VERSION 5.7 ;
  NOWIREEXTENSIONATPIN ON ;
  DIVIDERCHAR "/" ;
  BUSBITCHARS "[]" ;
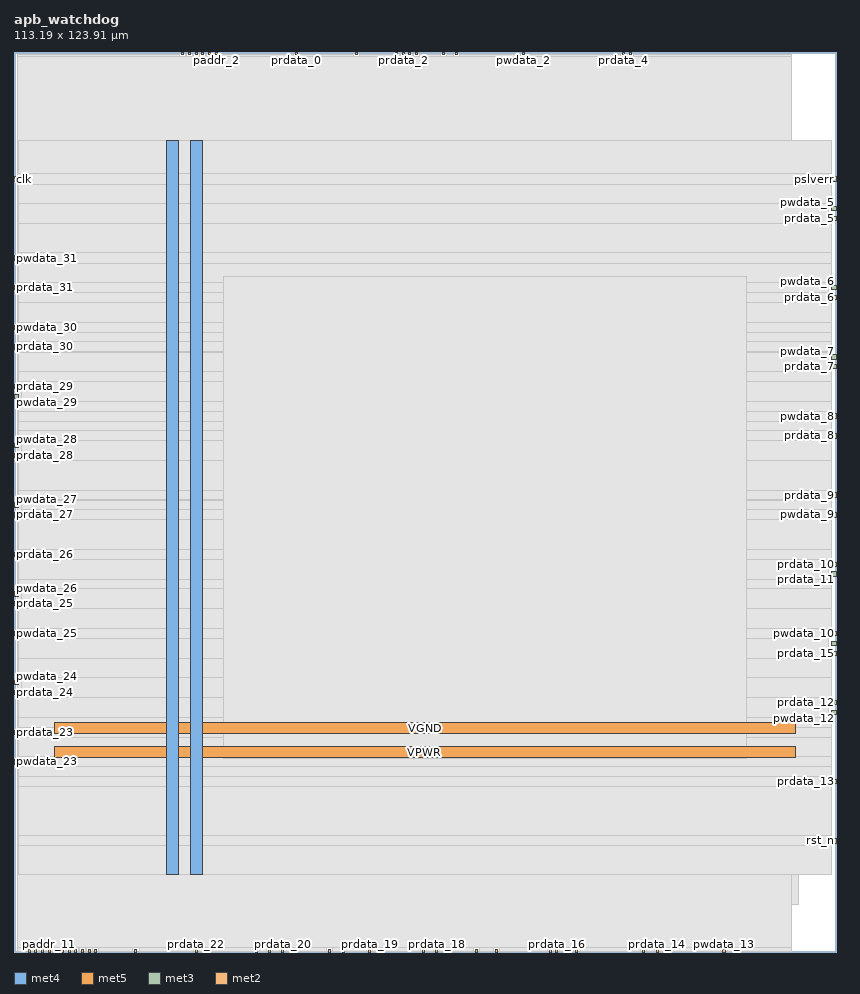
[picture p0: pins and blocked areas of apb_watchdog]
MACRO apb_watchdog
  CLASS BLOCK ;
  FOREIGN apb_watchdog ;
  ORIGIN 0.000 0.000 ;
  SIZE 113.190 BY 123.910 ;
  PIN VGND
    DIRECTION INOUT ;
    USE GROUND ;
    PORT
      LAYER met4 ;
        RECT 24.340 10.640 25.940 111.760 ;
    END
    PORT
      LAYER met5 ;
        RECT 5.520 30.030 107.640 31.630 ;
    END
  END VGND
  PIN VPWR
    DIRECTION INOUT ;
    USE POWER ;
    PORT
      LAYER met4 ;
        RECT 21.040 10.640 22.640 111.760 ;
    END
    PORT
      LAYER met5 ;
        RECT 5.520 26.730 107.640 28.330 ;
    END
  END VPWR
  PIN clk
    DIRECTION INPUT ;
    USE SIGNAL ;
    ANTENNAGATEAREA 1.286700 ;
    ANTENNADIFFAREA 0.434700 ;
    PORT
      LAYER met3 ;
        RECT 0.000 106.120 0.600 106.720 ;
    END
  END clk
  PIN paddr_0
    DIRECTION INPUT ;
    USE SIGNAL ;
    PORT
      LAYER met2 ;
        RECT 1.930 0.000 2.210 0.280 ;
    END
  END paddr_0
  PIN paddr_1
    DIRECTION INPUT ;
    USE SIGNAL ;
    PORT
      LAYER met2 ;
        RECT 2.850 0.000 3.130 0.280 ;
    END
  END paddr_1
  PIN paddr_10
    DIRECTION INPUT ;
    USE SIGNAL ;
    PORT
      LAYER met2 ;
        RECT 3.770 0.000 4.050 0.280 ;
    END
  END paddr_10
  PIN paddr_11
    DIRECTION INPUT ;
    USE SIGNAL ;
    PORT
      LAYER met2 ;
        RECT 4.690 0.000 4.970 0.280 ;
    END
  END paddr_11
  PIN paddr_2
    DIRECTION INPUT ;
    USE SIGNAL ;
    ANTENNAGATEAREA 0.647700 ;
    ANTENNADIFFAREA 0.434700 ;
    PORT
      LAYER met2 ;
        RECT 27.690 123.630 27.970 123.910 ;
    END
  END paddr_2
  PIN paddr_3
    DIRECTION INPUT ;
    USE SIGNAL ;
    ANTENNAGATEAREA 0.647700 ;
    ANTENNADIFFAREA 0.434700 ;
    PORT
      LAYER met2 ;
        RECT 26.770 123.630 27.050 123.910 ;
    END
  END paddr_3
  PIN paddr_4
    DIRECTION INPUT ;
    USE SIGNAL ;
    ANTENNAGATEAREA 0.647700 ;
    ANTENNADIFFAREA 0.434700 ;
    PORT
      LAYER met2 ;
        RECT 25.850 123.630 26.130 123.910 ;
    END
  END paddr_4
  PIN paddr_5
    DIRECTION INPUT ;
    USE SIGNAL ;
    PORT
      LAYER met2 ;
        RECT 5.610 0.000 5.890 0.280 ;
    END
  END paddr_5
  PIN paddr_6
    DIRECTION INPUT ;
    USE SIGNAL ;
    PORT
      LAYER met2 ;
        RECT 6.530 0.000 6.810 0.280 ;
    END
  END paddr_6
  PIN paddr_7
    DIRECTION INPUT ;
    USE SIGNAL ;
    PORT
      LAYER met2 ;
        RECT 7.450 0.000 7.730 0.280 ;
    END
  END paddr_7
  PIN paddr_8
    DIRECTION INPUT ;
    USE SIGNAL ;
    PORT
      LAYER met2 ;
        RECT 8.370 0.000 8.650 0.280 ;
    END
  END paddr_8
  PIN paddr_9
    DIRECTION INPUT ;
    USE SIGNAL ;
    PORT
      LAYER met2 ;
        RECT 9.290 0.000 9.570 0.280 ;
    END
  END paddr_9
  PIN penable
    DIRECTION INPUT ;
    USE SIGNAL ;
    ANTENNAGATEAREA 0.647700 ;
    ANTENNADIFFAREA 0.434700 ;
    PORT
      LAYER met2 ;
        RECT 24.010 123.630 24.290 123.910 ;
    END
  END penable
  PIN prdata_0
    DIRECTION OUTPUT ;
    USE SIGNAL ;
    ANTENNAGATEAREA 0.434700 ;
    ANTENNADIFFAREA 1.137600 ;
    PORT
      LAYER met2 ;
        RECT 38.730 123.630 39.010 123.910 ;
    END
  END prdata_0
  PIN prdata_1
    DIRECTION OUTPUT ;
    USE SIGNAL ;
    ANTENNAGATEAREA 0.434700 ;
    ANTENNADIFFAREA 1.137600 ;
    PORT
      LAYER met2 ;
        RECT 52.530 123.630 52.810 123.910 ;
    END
  END prdata_1
  PIN prdata_10
    DIRECTION OUTPUT ;
    USE SIGNAL ;
    ANTENNAGATEAREA 0.434700 ;
    ANTENNADIFFAREA 1.137600 ;
    PORT
      LAYER met3 ;
        RECT 112.590 53.080 113.190 53.680 ;
    END
  END prdata_10
  PIN prdata_11
    DIRECTION OUTPUT ;
    USE SIGNAL ;
    ANTENNAGATEAREA 0.434700 ;
    ANTENNADIFFAREA 1.137600 ;
    PORT
      LAYER met3 ;
        RECT 112.590 51.720 113.190 52.320 ;
    END
  END prdata_11
  PIN prdata_12
    DIRECTION OUTPUT ;
    USE SIGNAL ;
    ANTENNAGATEAREA 0.434700 ;
    ANTENNADIFFAREA 1.137600 ;
    PORT
      LAYER met3 ;
        RECT 112.590 34.040 113.190 34.640 ;
    END
  END prdata_12
  PIN prdata_13
    DIRECTION OUTPUT ;
    USE SIGNAL ;
    ANTENNAGATEAREA 0.434700 ;
    ANTENNADIFFAREA 1.137600 ;
    PORT
      LAYER met3 ;
        RECT 112.590 23.160 113.190 23.760 ;
    END
  END prdata_13
  PIN prdata_14
    DIRECTION OUTPUT ;
    USE SIGNAL ;
    ANTENNAGATEAREA 0.434700 ;
    ANTENNADIFFAREA 1.137600 ;
    PORT
      LAYER met2 ;
        RECT 88.410 0.000 88.690 0.280 ;
    END
  END prdata_14
  PIN prdata_15
    DIRECTION OUTPUT ;
    USE SIGNAL ;
    ANTENNAGATEAREA 0.434700 ;
    ANTENNADIFFAREA 1.137600 ;
    PORT
      LAYER met3 ;
        RECT 112.590 40.840 113.190 41.440 ;
    END
  END prdata_15
  PIN prdata_16
    DIRECTION OUTPUT ;
    USE SIGNAL ;
    ANTENNAGATEAREA 0.434700 ;
    ANTENNADIFFAREA 1.137600 ;
    PORT
      LAYER met2 ;
        RECT 74.610 0.000 74.890 0.280 ;
    END
  END prdata_16
  PIN prdata_17
    DIRECTION OUTPUT ;
    USE SIGNAL ;
    ANTENNAGATEAREA 0.434700 ;
    ANTENNADIFFAREA 1.137600 ;
    PORT
      LAYER met2 ;
        RECT 66.330 0.000 66.610 0.280 ;
    END
  END prdata_17
  PIN prdata_18
    DIRECTION OUTPUT ;
    USE SIGNAL ;
    ANTENNAGATEAREA 0.434700 ;
    ANTENNADIFFAREA 1.137600 ;
    PORT
      LAYER met2 ;
        RECT 58.050 0.000 58.330 0.280 ;
    END
  END prdata_18
  PIN prdata_19
    DIRECTION OUTPUT ;
    USE SIGNAL ;
    ANTENNAGATEAREA 0.434700 ;
    ANTENNADIFFAREA 1.137600 ;
    PORT
      LAYER met2 ;
        RECT 48.850 0.000 49.130 0.280 ;
    END
  END prdata_19
  PIN prdata_2
    DIRECTION OUTPUT ;
    USE SIGNAL ;
    ANTENNAGATEAREA 0.434700 ;
    ANTENNADIFFAREA 1.137600 ;
    PORT
      LAYER met2 ;
        RECT 53.450 123.630 53.730 123.910 ;
    END
  END prdata_2
  PIN prdata_20
    DIRECTION OUTPUT ;
    USE SIGNAL ;
    ANTENNAGATEAREA 0.434700 ;
    ANTENNADIFFAREA 1.137600 ;
    PORT
      LAYER met2 ;
        RECT 36.890 0.000 37.170 0.280 ;
    END
  END prdata_20
  PIN prdata_21
    DIRECTION OUTPUT ;
    USE SIGNAL ;
    ANTENNAGATEAREA 0.434700 ;
    ANTENNADIFFAREA 1.137600 ;
    PORT
      LAYER met2 ;
        RECT 43.330 0.000 43.610 0.280 ;
    END
  END prdata_21
  PIN prdata_22
    DIRECTION OUTPUT ;
    USE SIGNAL ;
    ANTENNAGATEAREA 0.434700 ;
    ANTENNADIFFAREA 1.137600 ;
    PORT
      LAYER met2 ;
        RECT 24.930 0.000 25.210 0.280 ;
    END
  END prdata_22
  PIN prdata_23
    DIRECTION OUTPUT ;
    USE SIGNAL ;
    ANTENNAGATEAREA 0.434700 ;
    ANTENNADIFFAREA 1.137600 ;
    PORT
      LAYER met3 ;
        RECT 0.000 29.960 0.600 30.560 ;
    END
  END prdata_23
  PIN prdata_24
    DIRECTION OUTPUT ;
    USE SIGNAL ;
    ANTENNAGATEAREA 0.434700 ;
    ANTENNADIFFAREA 1.137600 ;
    PORT
      LAYER met3 ;
        RECT 0.000 35.400 0.600 36.000 ;
    END
  END prdata_24
  PIN prdata_25
    DIRECTION OUTPUT ;
    USE SIGNAL ;
    ANTENNAGATEAREA 0.434700 ;
    ANTENNADIFFAREA 1.137600 ;
    PORT
      LAYER met3 ;
        RECT 0.000 47.640 0.600 48.240 ;
    END
  END prdata_25
  PIN prdata_26
    DIRECTION OUTPUT ;
    USE SIGNAL ;
    ANTENNAGATEAREA 0.434700 ;
    ANTENNADIFFAREA 1.137600 ;
    PORT
      LAYER met3 ;
        RECT 0.000 54.440 0.600 55.040 ;
    END
  END prdata_26
  PIN prdata_27
    DIRECTION OUTPUT ;
    USE SIGNAL ;
    ANTENNAGATEAREA 0.434700 ;
    ANTENNADIFFAREA 1.137600 ;
    PORT
      LAYER met3 ;
        RECT 0.000 59.880 0.600 60.480 ;
    END
  END prdata_27
  PIN prdata_28
    DIRECTION OUTPUT ;
    USE SIGNAL ;
    ANTENNAGATEAREA 0.434700 ;
    ANTENNADIFFAREA 1.137600 ;
    PORT
      LAYER met3 ;
        RECT 0.000 68.040 0.600 68.640 ;
    END
  END prdata_28
  PIN prdata_29
    DIRECTION OUTPUT ;
    USE SIGNAL ;
    ANTENNAGATEAREA 0.434700 ;
    ANTENNADIFFAREA 1.137600 ;
    PORT
      LAYER met3 ;
        RECT 0.000 77.560 0.600 78.160 ;
    END
  END prdata_29
  PIN prdata_3
    DIRECTION OUTPUT ;
    USE SIGNAL ;
    ANTENNAGATEAREA 0.434700 ;
    ANTENNADIFFAREA 1.137600 ;
    PORT
      LAYER met2 ;
        RECT 55.290 123.630 55.570 123.910 ;
    END
  END prdata_3
  PIN prdata_30
    DIRECTION OUTPUT ;
    USE SIGNAL ;
    ANTENNAGATEAREA 0.434700 ;
    ANTENNADIFFAREA 1.137600 ;
    PORT
      LAYER met3 ;
        RECT 0.000 83.000 0.600 83.600 ;
    END
  END prdata_30
  PIN prdata_31
    DIRECTION OUTPUT ;
    USE SIGNAL ;
    ANTENNAGATEAREA 0.434700 ;
    ANTENNADIFFAREA 1.137600 ;
    PORT
      LAYER met3 ;
        RECT 0.000 91.160 0.600 91.760 ;
    END
  END prdata_31
  PIN prdata_4
    DIRECTION OUTPUT ;
    USE SIGNAL ;
    ANTENNAGATEAREA 0.434700 ;
    ANTENNADIFFAREA 1.137600 ;
    PORT
      LAYER met2 ;
        RECT 83.810 123.630 84.090 123.910 ;
    END
  END prdata_4
  PIN prdata_5
    DIRECTION OUTPUT ;
    USE SIGNAL ;
    ANTENNAGATEAREA 0.434700 ;
    ANTENNADIFFAREA 1.137600 ;
    PORT
      LAYER met3 ;
        RECT 112.590 100.680 113.190 101.280 ;
    END
  END prdata_5
  PIN prdata_6
    DIRECTION OUTPUT ;
    USE SIGNAL ;
    ANTENNAGATEAREA 0.434700 ;
    ANTENNADIFFAREA 1.137600 ;
    PORT
      LAYER met3 ;
        RECT 112.590 89.800 113.190 90.400 ;
    END
  END prdata_6
  PIN prdata_7
    DIRECTION OUTPUT ;
    USE SIGNAL ;
    ANTENNAGATEAREA 0.434700 ;
    ANTENNADIFFAREA 1.137600 ;
    PORT
      LAYER met3 ;
        RECT 112.590 80.280 113.190 80.880 ;
    END
  END prdata_7
  PIN prdata_8
    DIRECTION OUTPUT ;
    USE SIGNAL ;
    ANTENNAGATEAREA 0.434700 ;
    ANTENNADIFFAREA 1.137600 ;
    PORT
      LAYER met3 ;
        RECT 112.590 70.760 113.190 71.360 ;
    END
  END prdata_8
  PIN prdata_9
    DIRECTION OUTPUT ;
    USE SIGNAL ;
    ANTENNAGATEAREA 0.434700 ;
    ANTENNADIFFAREA 1.137600 ;
    PORT
      LAYER met3 ;
        RECT 112.590 62.600 113.190 63.200 ;
    END
  END prdata_9
  PIN pready
    DIRECTION OUTPUT ;
    USE SIGNAL ;
    PORT
      LAYER met2 ;
        RECT 10.210 0.000 10.490 0.280 ;
    END
  END pready
  PIN psel
    DIRECTION INPUT ;
    USE SIGNAL ;
    ANTENNAGATEAREA 0.647700 ;
    ANTENNADIFFAREA 0.434700 ;
    PORT
      LAYER met2 ;
        RECT 24.930 123.630 25.210 123.910 ;
    END
  END psel
  PIN pslverr
    DIRECTION OUTPUT ;
    USE SIGNAL ;
    ANTENNAGATEAREA 0.434700 ;
    ANTENNADIFFAREA 0.775300 ;
    PORT
      LAYER met3 ;
        RECT 112.590 106.120 113.190 106.720 ;
    END
  END pslverr
  PIN pwdata_0
    DIRECTION INPUT ;
    USE SIGNAL ;
    ANTENNAGATEAREA 0.647700 ;
    ANTENNADIFFAREA 0.434700 ;
    PORT
      LAYER met2 ;
        RECT 54.370 123.630 54.650 123.910 ;
    END
  END pwdata_0
  PIN pwdata_1
    DIRECTION INPUT ;
    USE SIGNAL ;
    ANTENNAGATEAREA 0.647700 ;
    ANTENNADIFFAREA 0.434700 ;
    PORT
      LAYER met2 ;
        RECT 60.810 123.630 61.090 123.910 ;
    END
  END pwdata_1
  PIN pwdata_10
    DIRECTION INPUT ;
    USE SIGNAL ;
    ANTENNAGATEAREA 0.647700 ;
    ANTENNADIFFAREA 0.434700 ;
    PORT
      LAYER met3 ;
        RECT 112.590 43.560 113.190 44.160 ;
    END
  END pwdata_10
  PIN pwdata_11
    DIRECTION INPUT ;
    USE SIGNAL ;
    ANTENNAGATEAREA 0.647700 ;
    ANTENNADIFFAREA 0.434700 ;
    PORT
      LAYER met3 ;
        RECT 112.590 42.200 113.190 42.800 ;
    END
  END pwdata_11
  PIN pwdata_12
    DIRECTION INPUT ;
    USE SIGNAL ;
    ANTENNAGATEAREA 0.647700 ;
    ANTENNADIFFAREA 0.434700 ;
    PORT
      LAYER met3 ;
        RECT 112.590 32.680 113.190 33.280 ;
    END
  END pwdata_12
  PIN pwdata_13
    DIRECTION INPUT ;
    USE SIGNAL ;
    ANTENNAGATEAREA 0.647700 ;
    ANTENNADIFFAREA 0.434700 ;
    PORT
      LAYER met2 ;
        RECT 97.610 0.000 97.890 0.280 ;
    END
  END pwdata_13
  PIN pwdata_14
    DIRECTION INPUT ;
    USE SIGNAL ;
    ANTENNAGATEAREA 0.647700 ;
    ANTENNADIFFAREA 0.434700 ;
    PORT
      LAYER met2 ;
        RECT 86.570 0.000 86.850 0.280 ;
    END
  END pwdata_14
  PIN pwdata_15
    DIRECTION INPUT ;
    USE SIGNAL ;
    ANTENNAGATEAREA 0.647700 ;
    ANTENNADIFFAREA 0.434700 ;
    PORT
      LAYER met2 ;
        RECT 77.370 0.000 77.650 0.280 ;
    END
  END pwdata_15
  PIN pwdata_16
    DIRECTION INPUT ;
    USE SIGNAL ;
    ANTENNAGATEAREA 0.647700 ;
    ANTENNADIFFAREA 0.434700 ;
    PORT
      LAYER met2 ;
        RECT 73.690 0.000 73.970 0.280 ;
    END
  END pwdata_16
  PIN pwdata_17
    DIRECTION INPUT ;
    USE SIGNAL ;
    ANTENNAGATEAREA 0.647700 ;
    ANTENNADIFFAREA 0.434700 ;
    PORT
      LAYER met2 ;
        RECT 63.570 0.000 63.850 0.280 ;
    END
  END pwdata_17
  PIN pwdata_18
    DIRECTION INPUT ;
    USE SIGNAL ;
    ANTENNAGATEAREA 0.647700 ;
    ANTENNADIFFAREA 0.434700 ;
    PORT
      LAYER met2 ;
        RECT 56.210 0.000 56.490 0.280 ;
    END
  END pwdata_18
  PIN pwdata_19
    DIRECTION INPUT ;
    USE SIGNAL ;
    ANTENNAGATEAREA 0.647700 ;
    ANTENNADIFFAREA 0.434700 ;
    PORT
      LAYER met2 ;
        RECT 45.170 0.000 45.450 0.280 ;
    END
  END pwdata_19
  PIN pwdata_2
    DIRECTION INPUT ;
    USE SIGNAL ;
    ANTENNAGATEAREA 0.647700 ;
    ANTENNADIFFAREA 0.434700 ;
    PORT
      LAYER met2 ;
        RECT 70.010 123.630 70.290 123.910 ;
    END
  END pwdata_2
  PIN pwdata_20
    DIRECTION INPUT ;
    USE SIGNAL ;
    ANTENNAGATEAREA 0.647700 ;
    ANTENNADIFFAREA 0.434700 ;
    PORT
      LAYER met2 ;
        RECT 33.210 0.000 33.490 0.280 ;
    END
  END pwdata_20
  PIN pwdata_21
    DIRECTION INPUT ;
    USE SIGNAL ;
    ANTENNAGATEAREA 0.647700 ;
    ANTENNADIFFAREA 0.434700 ;
    PORT
      LAYER met2 ;
        RECT 35.050 0.000 35.330 0.280 ;
    END
  END pwdata_21
  PIN pwdata_22
    DIRECTION INPUT ;
    USE SIGNAL ;
    ANTENNAGATEAREA 0.647700 ;
    ANTENNADIFFAREA 0.434700 ;
    PORT
      LAYER met2 ;
        RECT 16.650 0.000 16.930 0.280 ;
    END
  END pwdata_22
  PIN pwdata_23
    DIRECTION INPUT ;
    USE SIGNAL ;
    ANTENNAGATEAREA 0.647700 ;
    ANTENNADIFFAREA 0.434700 ;
    PORT
      LAYER met3 ;
        RECT 0.000 25.880 0.600 26.480 ;
    END
  END pwdata_23
  PIN pwdata_24
    DIRECTION INPUT ;
    USE SIGNAL ;
    ANTENNAGATEAREA 0.647700 ;
    ANTENNADIFFAREA 0.434700 ;
    PORT
      LAYER met3 ;
        RECT 0.000 36.760 0.600 37.360 ;
    END
  END pwdata_24
  PIN pwdata_25
    DIRECTION INPUT ;
    USE SIGNAL ;
    ANTENNAGATEAREA 0.647700 ;
    ANTENNADIFFAREA 0.434700 ;
    PORT
      LAYER met3 ;
        RECT 0.000 43.560 0.600 44.160 ;
    END
  END pwdata_25
  PIN pwdata_26
    DIRECTION INPUT ;
    USE SIGNAL ;
    ANTENNAGATEAREA 0.647700 ;
    ANTENNADIFFAREA 0.434700 ;
    PORT
      LAYER met3 ;
        RECT 0.000 49.000 0.600 49.600 ;
    END
  END pwdata_26
  PIN pwdata_27
    DIRECTION INPUT ;
    USE SIGNAL ;
    ANTENNAGATEAREA 0.647700 ;
    ANTENNADIFFAREA 0.434700 ;
    PORT
      LAYER met3 ;
        RECT 0.000 61.240 0.600 61.840 ;
    END
  END pwdata_27
  PIN pwdata_28
    DIRECTION INPUT ;
    USE SIGNAL ;
    ANTENNAGATEAREA 0.647700 ;
    ANTENNADIFFAREA 0.434700 ;
    PORT
      LAYER met3 ;
        RECT 0.000 69.400 0.600 70.000 ;
    END
  END pwdata_28
  PIN pwdata_29
    DIRECTION INPUT ;
    USE SIGNAL ;
    ANTENNAGATEAREA 0.647700 ;
    ANTENNADIFFAREA 0.434700 ;
    PORT
      LAYER met3 ;
        RECT 0.000 76.200 0.600 76.800 ;
    END
  END pwdata_29
  PIN pwdata_3
    DIRECTION INPUT ;
    USE SIGNAL ;
    ANTENNAGATEAREA 0.647700 ;
    ANTENNADIFFAREA 0.434700 ;
    PORT
      LAYER met2 ;
        RECT 58.970 123.630 59.250 123.910 ;
    END
  END pwdata_3
  PIN pwdata_30
    DIRECTION INPUT ;
    USE SIGNAL ;
    ANTENNAGATEAREA 0.647700 ;
    ANTENNADIFFAREA 0.434700 ;
    PORT
      LAYER met3 ;
        RECT 0.000 85.720 0.600 86.320 ;
    END
  END pwdata_30
  PIN pwdata_31
    DIRECTION INPUT ;
    USE SIGNAL ;
    ANTENNAGATEAREA 0.647700 ;
    ANTENNADIFFAREA 0.434700 ;
    PORT
      LAYER met3 ;
        RECT 0.000 95.240 0.600 95.840 ;
    END
  END pwdata_31
  PIN pwdata_4
    DIRECTION INPUT ;
    USE SIGNAL ;
    ANTENNAGATEAREA 0.647700 ;
    ANTENNADIFFAREA 0.434700 ;
    PORT
      LAYER met2 ;
        RECT 84.730 123.630 85.010 123.910 ;
    END
  END pwdata_4
  PIN pwdata_5
    DIRECTION INPUT ;
    USE SIGNAL ;
    ANTENNAGATEAREA 0.647700 ;
    ANTENNADIFFAREA 0.434700 ;
    PORT
      LAYER met3 ;
        RECT 112.590 102.040 113.190 102.640 ;
    END
  END pwdata_5
  PIN pwdata_6
    DIRECTION INPUT ;
    USE SIGNAL ;
    ANTENNAGATEAREA 0.647700 ;
    ANTENNADIFFAREA 0.434700 ;
    PORT
      LAYER met3 ;
        RECT 112.590 91.160 113.190 91.760 ;
    END
  END pwdata_6
  PIN pwdata_7
    DIRECTION INPUT ;
    USE SIGNAL ;
    ANTENNAGATEAREA 0.647700 ;
    ANTENNADIFFAREA 0.434700 ;
    PORT
      LAYER met3 ;
        RECT 112.590 81.640 113.190 82.240 ;
    END
  END pwdata_7
  PIN pwdata_8
    DIRECTION INPUT ;
    USE SIGNAL ;
    ANTENNAGATEAREA 0.647700 ;
    ANTENNADIFFAREA 0.434700 ;
    PORT
      LAYER met3 ;
        RECT 112.590 73.480 113.190 74.080 ;
    END
  END pwdata_8
  PIN pwdata_9
    DIRECTION INPUT ;
    USE SIGNAL ;
    ANTENNAGATEAREA 0.647700 ;
    ANTENNADIFFAREA 0.434700 ;
    PORT
      LAYER met3 ;
        RECT 112.590 59.880 113.190 60.480 ;
    END
  END pwdata_9
  PIN pwrite
    DIRECTION INPUT ;
    USE SIGNAL ;
    ANTENNAGATEAREA 0.647700 ;
    ANTENNADIFFAREA 0.434700 ;
    PORT
      LAYER met2 ;
        RECT 23.090 123.630 23.370 123.910 ;
    END
  END pwrite
  PIN rst_n
    DIRECTION INPUT ;
    USE SIGNAL ;
    ANTENNAGATEAREA 0.647700 ;
    ANTENNADIFFAREA 0.434700 ;
    PORT
      LAYER met3 ;
        RECT 112.590 15.000 113.190 15.600 ;
    END
  END rst_n
  PIN wdt_irq
    DIRECTION OUTPUT ;
    USE SIGNAL ;
    ANTENNAGATEAREA 0.434700 ;
    ANTENNADIFFAREA 1.137600 ;
    PORT
      LAYER met2 ;
        RECT 47.010 123.630 47.290 123.910 ;
    END
  END wdt_irq
  PIN wdt_reset
    DIRECTION OUTPUT ;
    USE SIGNAL ;
    PORT
      LAYER met2 ;
        RECT 11.130 0.000 11.410 0.280 ;
    END
  END wdt_reset
  OBS
      LAYER nwell ;
        RECT 5.330 10.795 107.830 111.710 ;
      LAYER li1 ;
        RECT 5.520 10.795 107.640 111.605 ;
      LAYER met1 ;
        RECT 0.530 6.500 107.940 111.760 ;
      LAYER met2 ;
        RECT 0.550 123.350 22.810 123.630 ;
        RECT 23.650 123.350 23.730 123.630 ;
        RECT 24.570 123.350 24.650 123.630 ;
        RECT 25.490 123.350 25.570 123.630 ;
        RECT 26.410 123.350 26.490 123.630 ;
        RECT 27.330 123.350 27.410 123.630 ;
        RECT 28.250 123.350 38.450 123.630 ;
        RECT 39.290 123.350 46.730 123.630 ;
        RECT 47.570 123.350 52.250 123.630 ;
        RECT 53.090 123.350 53.170 123.630 ;
        RECT 54.010 123.350 54.090 123.630 ;
        RECT 54.930 123.350 55.010 123.630 ;
        RECT 55.850 123.350 58.690 123.630 ;
        RECT 59.530 123.350 60.530 123.630 ;
        RECT 61.370 123.350 69.730 123.630 ;
        RECT 70.570 123.350 83.530 123.630 ;
        RECT 84.370 123.350 84.450 123.630 ;
        RECT 85.290 123.350 107.090 123.630 ;
        RECT 0.550 0.560 107.090 123.350 ;
        RECT 0.550 0.070 1.650 0.560 ;
        RECT 2.490 0.070 2.570 0.560 ;
        RECT 3.410 0.070 3.490 0.560 ;
        RECT 4.330 0.070 4.410 0.560 ;
        RECT 5.250 0.070 5.330 0.560 ;
        RECT 6.170 0.070 6.250 0.560 ;
        RECT 7.090 0.070 7.170 0.560 ;
        RECT 8.010 0.070 8.090 0.560 ;
        RECT 8.930 0.070 9.010 0.560 ;
        RECT 9.850 0.070 9.930 0.560 ;
        RECT 10.770 0.070 10.850 0.560 ;
        RECT 11.690 0.070 16.370 0.560 ;
        RECT 17.210 0.070 24.650 0.560 ;
        RECT 25.490 0.070 32.930 0.560 ;
        RECT 33.770 0.070 34.770 0.560 ;
        RECT 35.610 0.070 36.610 0.560 ;
        RECT 37.450 0.070 43.050 0.560 ;
        RECT 43.890 0.070 44.890 0.560 ;
        RECT 45.730 0.070 48.570 0.560 ;
        RECT 49.410 0.070 55.930 0.560 ;
        RECT 56.770 0.070 57.770 0.560 ;
        RECT 58.610 0.070 63.290 0.560 ;
        RECT 64.130 0.070 66.050 0.560 ;
        RECT 66.890 0.070 73.410 0.560 ;
        RECT 74.250 0.070 74.330 0.560 ;
        RECT 75.170 0.070 77.090 0.560 ;
        RECT 77.930 0.070 86.290 0.560 ;
        RECT 87.130 0.070 88.130 0.560 ;
        RECT 88.970 0.070 97.330 0.560 ;
        RECT 98.170 0.070 107.090 0.560 ;
      LAYER met3 ;
        RECT 0.600 107.120 112.590 111.685 ;
        RECT 1.000 105.720 112.190 107.120 ;
        RECT 0.600 103.040 112.590 105.720 ;
        RECT 0.600 100.280 112.190 103.040 ;
        RECT 0.600 96.240 112.590 100.280 ;
        RECT 1.000 94.840 112.590 96.240 ;
        RECT 0.600 92.160 112.590 94.840 ;
        RECT 1.000 90.760 112.190 92.160 ;
        RECT 0.600 89.400 112.190 90.760 ;
        RECT 0.600 86.720 112.590 89.400 ;
        RECT 1.000 85.320 112.590 86.720 ;
        RECT 0.600 84.000 112.590 85.320 ;
        RECT 1.000 82.640 112.590 84.000 ;
        RECT 1.000 82.600 112.190 82.640 ;
        RECT 0.600 79.880 112.190 82.600 ;
        RECT 0.600 78.560 112.590 79.880 ;
        RECT 1.000 75.800 112.590 78.560 ;
        RECT 0.600 74.480 112.590 75.800 ;
        RECT 0.600 73.080 112.190 74.480 ;
        RECT 0.600 71.760 112.590 73.080 ;
        RECT 0.600 70.400 112.190 71.760 ;
        RECT 1.000 70.360 112.190 70.400 ;
        RECT 1.000 67.640 112.590 70.360 ;
        RECT 0.600 63.600 112.590 67.640 ;
        RECT 0.600 62.240 112.190 63.600 ;
        RECT 1.000 62.200 112.190 62.240 ;
        RECT 1.000 60.880 112.590 62.200 ;
        RECT 1.000 59.480 112.190 60.880 ;
        RECT 0.600 55.440 112.590 59.480 ;
        RECT 1.000 54.080 112.590 55.440 ;
        RECT 1.000 54.040 112.190 54.080 ;
        RECT 0.600 51.320 112.190 54.040 ;
        RECT 0.600 50.000 112.590 51.320 ;
        RECT 1.000 47.240 112.590 50.000 ;
        RECT 0.600 44.560 112.590 47.240 ;
        RECT 1.000 43.160 112.190 44.560 ;
        RECT 0.600 40.440 112.190 43.160 ;
        RECT 0.600 37.760 112.590 40.440 ;
        RECT 1.000 35.040 112.590 37.760 ;
        RECT 1.000 35.000 112.190 35.040 ;
        RECT 0.600 32.280 112.190 35.000 ;
        RECT 0.600 30.960 112.590 32.280 ;
        RECT 1.000 29.560 112.590 30.960 ;
        RECT 0.600 26.880 112.590 29.560 ;
        RECT 1.000 25.480 112.590 26.880 ;
        RECT 0.600 24.160 112.590 25.480 ;
        RECT 0.600 22.760 112.190 24.160 ;
        RECT 0.600 16.000 112.590 22.760 ;
        RECT 0.600 14.600 112.190 16.000 ;
        RECT 0.600 10.715 112.590 14.600 ;
      LAYER met4 ;
        RECT 28.815 26.695 100.905 92.985 ;
  END
END apb_watchdog
END LIBRARY

